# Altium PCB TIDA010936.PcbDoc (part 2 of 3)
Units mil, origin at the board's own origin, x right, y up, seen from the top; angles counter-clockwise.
Board outline 2755.91 x 2708.83 mil, 4 copper layers (Top Layer, POWER, GND, Bottom Layer), stack 64.224 mil thick; 224 components, 104 nets, 583 pads, 419 vias.

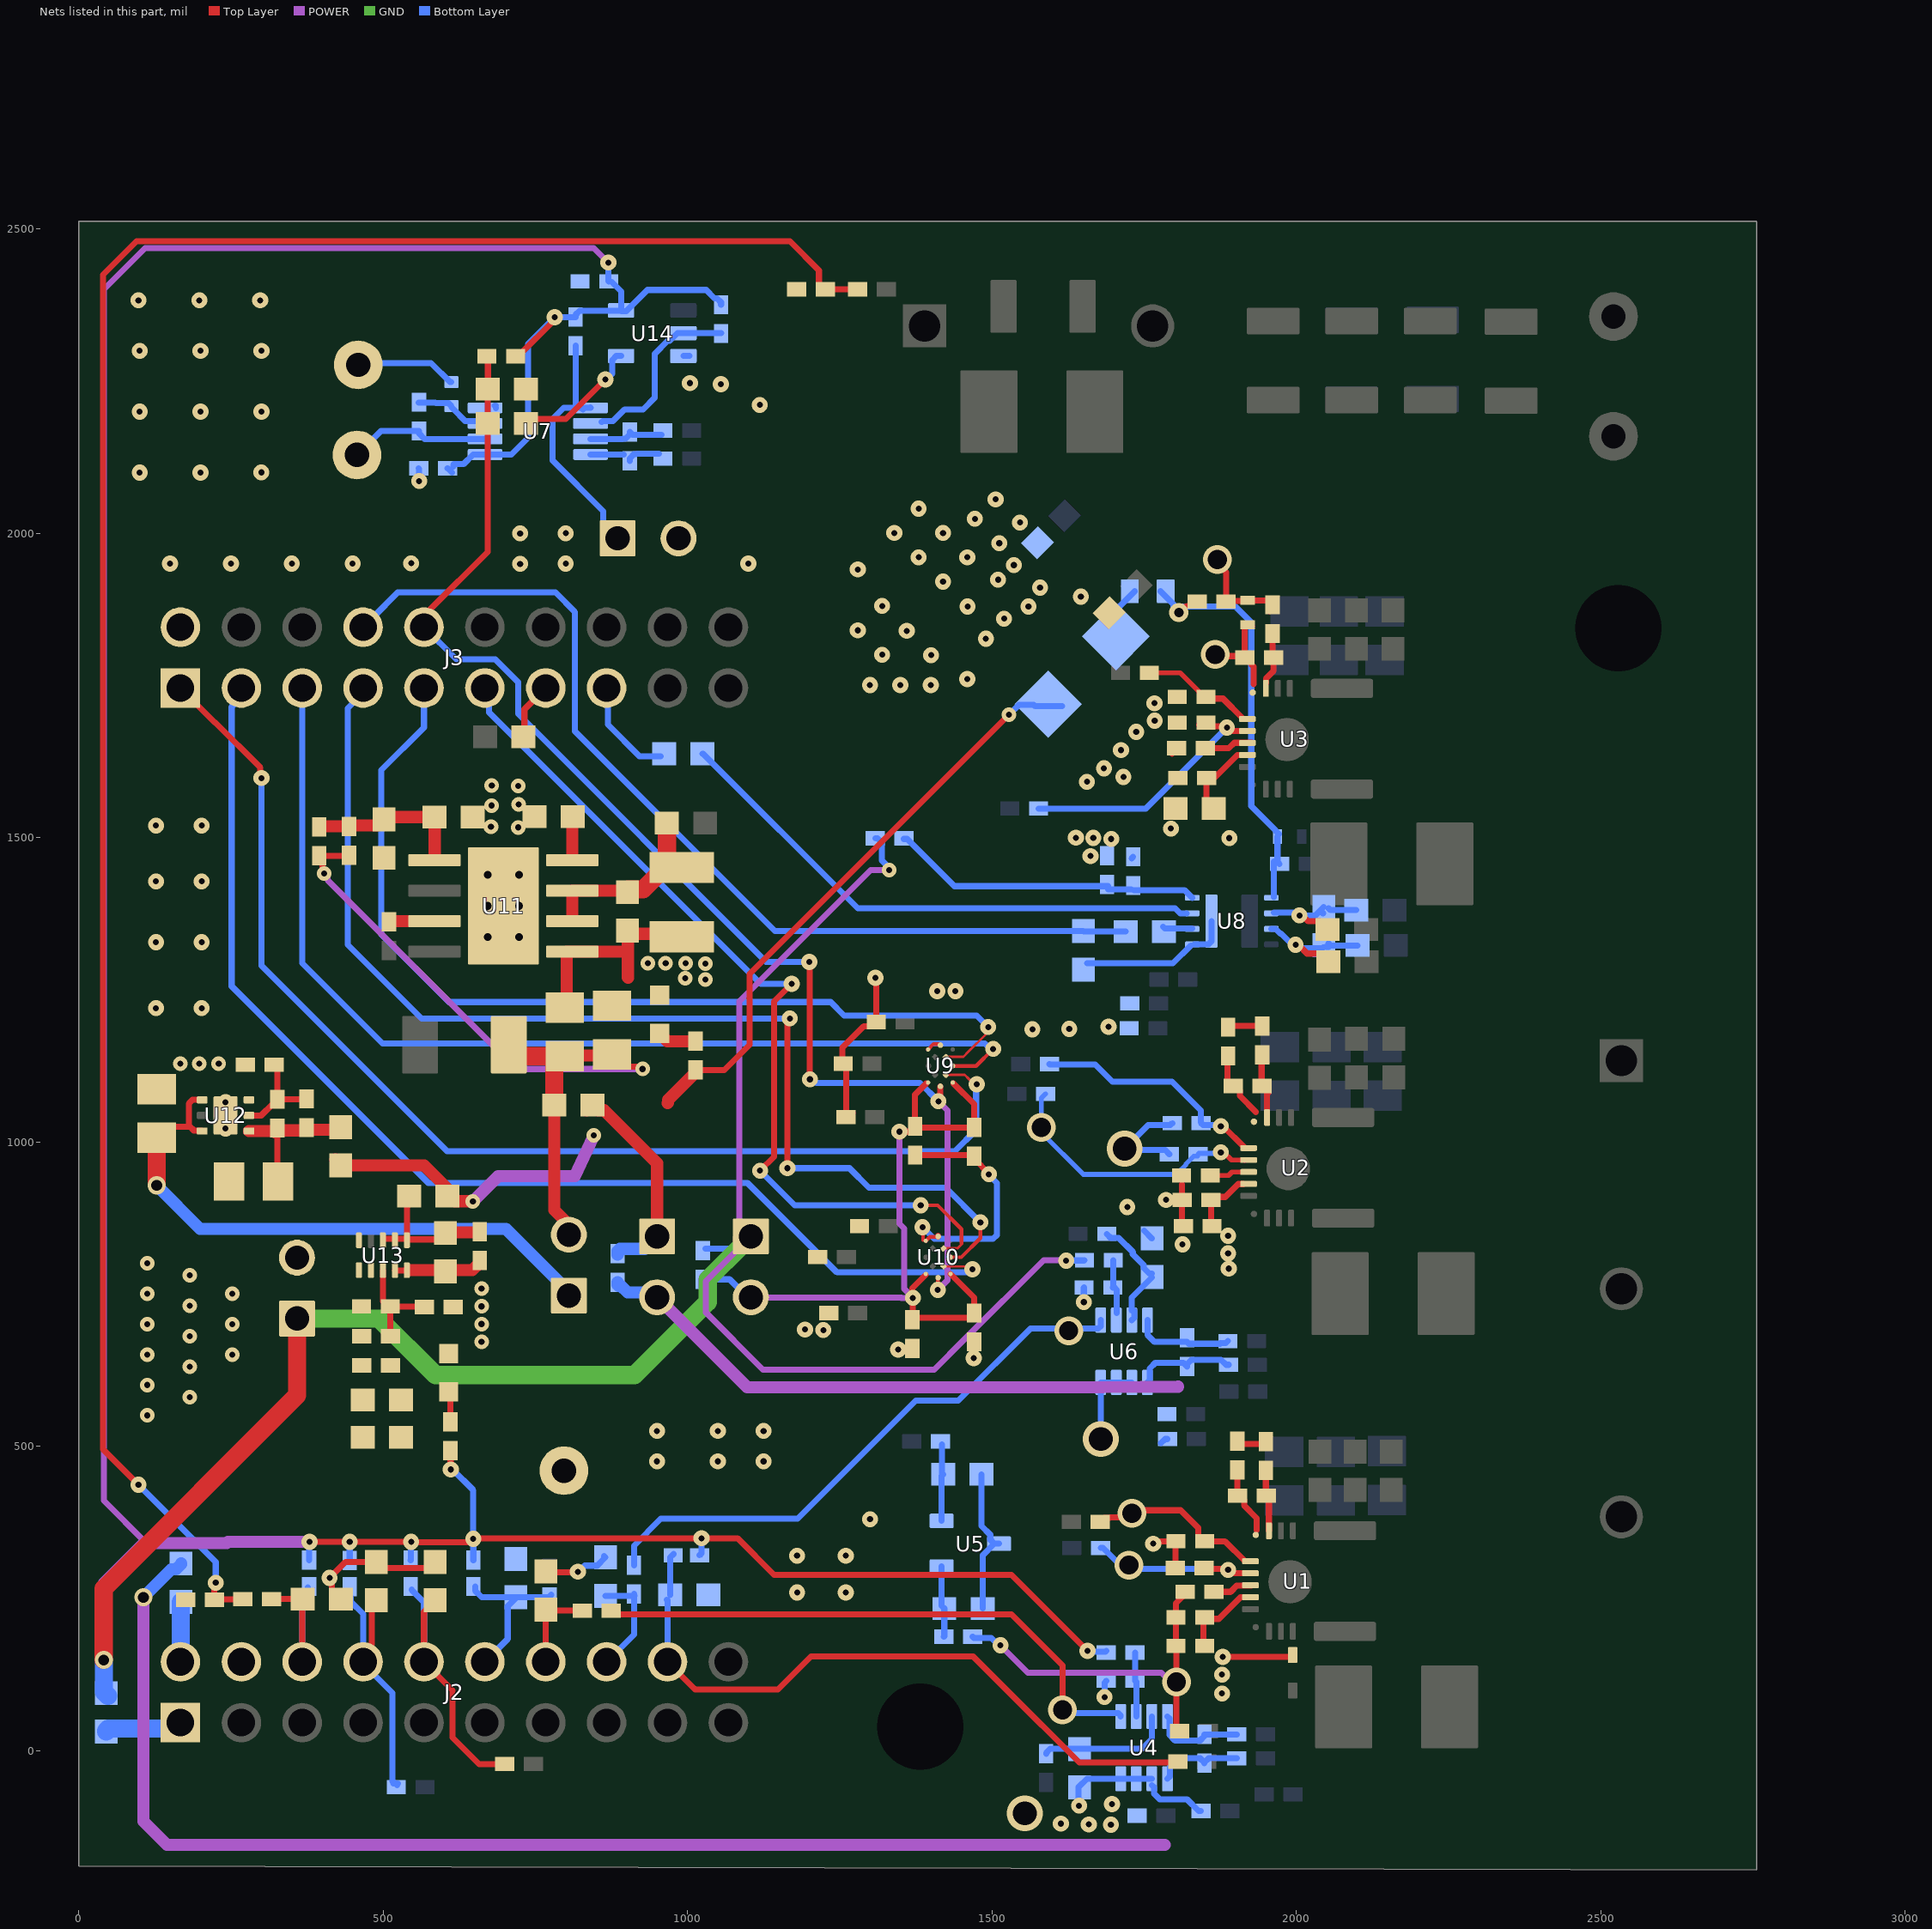
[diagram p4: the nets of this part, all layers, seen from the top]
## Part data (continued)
J1 J4 J7 J8: "Header, 100mil, 2x1, Tin, TH", Color=Black, Current_A=3A, Manufacturer="Sullins Connector Solutions", PartNumber=PEC02SAAN, Supplier Part Number 1=S1012E-02-ND, Voltage_V=1.8kV
J2 J3: "Connector, Receptacle, 100mil, 10x2, Gold plated, TH", Manufacturer=Samtec, PartNumber=SSW-110-23-F-D
J5: library part CMP-0055528-1, "Terminal Block, 9.52mm, 3x1, R/A, TH", Color=Green, Current_A=32A, Manufacturer="Phoenix Contact", PartNumber=1904150, Supplier Part Number 1=277-6184-ND, Voltage_V=1kV
J6: library part CMP-0055527-1, "Terminal Block, 9.52mm, 2x1, R/A, TH", Color=Green, Current_A=32A, Manufacturer="Phoenix Contact", PartNumber=1902547, Supplier Part Number 1=277-5951-ND, Voltage_V=1kV
J9: library part CMP-0002337-1, "Header, 100mil, 2x1, Tin, TH", Color=Black, Current_A=3A, Manufacturer="Sullins Connector Solutions", PartNumber=PEC02SAAN, Supplier Part Number 1=S1012E-02-ND, Voltage_V=1.8kV
L1 L2 L3: "Ferrite Bead, 300 ohm @ 100 MHz, 0.2 A, 0402", Manufacturer="Wurth Elektronik", PartNumber=74279272, Supplier Part Number 1=732-1572-1-ND, Value1="0.8 ohm", Value2=0.2A, ValueDisplayed="300 ohm"
L4: library part CMP-0064489-2, "Inductor, Shielded Drum Core, Powdered Iron, 22 uH, 1 A, 0.47 ohm, SMD", Manufacturer="Wurth Elektronik", Supplier Part Number 1=732-3340-1-ND, Value1="0.47 ohm", Value2=1A, ValueDisplayed=22uH
LBL1: library part CMP-0003625-1, "Thermal Transfer Printable Labels, 0.650\" W x 0.200\" H - 10,000 per roll", Manufacturer=Brady, Supplier Part Number 1=97C5133
NT1 NT2: "Single point connection between nets.", Manufacturer=N/A
R1 R18 R26 R39: library part CMP-0042666-1, "Res Metal Strip 2512 0.001 Ohm 1% 3W ±50ppm/C Pad SMD Automotive T/R", Manufacturer="TT Electronics", Mouser Part Number=66-ULRG3R001FLFSLT, Operating Temperature Range=to, Power_W=3W, Tempco=50ppm/°C, Tolerance_%=1%
R3 R4 R5 R13 R14 R23 R24 R25 R28 R30 R31 R32 R35 R36 R37 R52: "RES, 0, 5%, 0.063 W, AEC-Q200 Grade 0, 0402", Manufacturer=Vishay-Dale, PartNumber=CRCW04020000Z0ED, Power_W=63mW, Supplier Part Number 1=541-0.0JCT-ND, Tempco="200 ppm/C", Tolerance_%=5%, Value2=0.063W, Value_Code=0000, ValueDisplayed=0
R6 R7 R15: library part CMP-0026925-3, "RES, 3.0, 5%, 0.063 W, AEC-Q200 Grade 0, 0402", Manufacturer=Vishay-Dale, Power_W=63mW, Supplier Part Number 1=541-3.0JCT-ND, Tempco="200 ppm/C", Tolerance_%=5%, Value2=0.063W, Value_Code=3R00, ValueDisplayed=3.0
R8 R9 R10 R11 R16 R17: "RES, 20.0, 1%, 0.063 W, AEC-Q200 Grade 0, 0402", Manufacturer=Vishay-Dale, PartNumber=CRCW040220R0FKED, Power_W=63mW, Supplier Part Number 1=541-20.0LCT-ND, Tempco="100 ppm/C", Tolerance_%=1%, Value2=0.063W, Value_Code=20R0, ValueDisplayed=20.0
R12 R43 R58 R59 R60 R61 R62 R63 R70 R79: "RES, 10 k, 5%, 0.063 W, AEC-Q200 Grade 0, 0402", Manufacturer=Vishay-Dale, PartNumber=CRCW040210K0JNED, Power_W=63mW, Supplier Part Number 1=541-10KJCT-ND, Tempco="200 ppm/C", Tolerance_%=5%, Value2=0.063W, Value_Code=10k0, ValueDisplayed=10k
R19 R20 R27 R42: "RES, 100 k, 1%, 0.063 W, AEC-Q200 Grade 0, 0402", Manufacturer=Vishay-Dale, PartNumber=CRCW0402100KFKED, Power_W=63mW, Supplier Part Number 1=541-100KLCT-ND, Tempco="100 ppm/C", Tolerance_%=1%, Value2=0.063W, Value_Code=100k
R21 R22 R29 R46: "RES, 4.22 k, 1%, 0.063 W, AEC-Q200 Grade 0, 0402", Manufacturer=Vishay-Dale, PartNumber=CRCW04024K22FKED, Power_W=63mW, Supplier Part Number 1=541-4.22KLCT-ND, Tempco="100 ppm/C", Tolerance_%=1%, Value2=0.063W, Value_Code=4k22, ValueDisplayed=4.22k
R33: library part CMP-0026041-3, "RES, 16.5 k, 1%, 0.063 W, AEC-Q200 Grade 0, 0402", Manufacturer=Vishay-Dale, Power_W=63mW, Supplier Part Number 1=541-16.5KLCT-ND, Tempco="100 ppm/C", Tolerance_%=1%, Value2=0.063W, Value_Code=16k5, ValueDisplayed=16.5k
R34: library part CMP-0096630-1, "RES Thick Film, 3Ω, 1%, 0.33W, 100ppm/°C, 0603", Manufacturer=Vishay, Operating Temperature Range="-55°C to +155°C", Power=250mW, Power_W=330mW, Tempco=100ppm/°C, Tolerance_%=1%
R38: library part CMP-0093921-1, "11 kOhms ±1% 0.063W, 1/16W Chip Resistor 0402 (1005 Metric) Automotive AEC-Q200 Thick Film", Digikey Part Number=RMCF0402FT11K0CT-ND, Manufacturer=Stackpole, Operating Temperature Range="-55°C to +155°C", Power_W=63mW, Tempco=100ppm/°C, Tolerance_%=1%
R40 R56 R80: library part CMP-0022479-4, "RES, 50, 1%, 0.1 W, AEC-Q200 Grade 0, 0603", Manufacturer=Vishay-Dale, Power_W=100mW, Supplier Part Number 1=89M6778, Tempco="100 ppm/C", Tolerance_%=1%, Value2=0.1W, Value_Code=50R0, ValueDisplayed=50
R41 R45: library part CMP-0022004-2, "RES, 10.0, 1%, 0.25 W, 0603", Manufacturer=Vishay-Dale, Power_W=250mW, Supplier Part Number 1=541-10.0SCT-ND, Tempco="100 ppm/C", Tolerance_%=1%, Value2=0.25W, Value_Code=10R0, ValueDisplayed=10.0
R44: library part CMP-0025899-5, "RES, 1.0 k, 5%, 0.1 W, 0603", Manufacturer=Yageo, Power_W=100mW, Supplier Part Number 1=311-1.0KGRCT-ND, Tempco="100 ppm/C", Tolerance_%=5%, Value2=0.1W, Value_Code=1k00, ValueDisplayed=1.0k
R47 R48 R64 R65 R72 R73: library part CMP-0086358-1, "RES, 0, 0%, 0.25 W, AEC-Q200 Grade 0, 0603", Manufacturer=Rohm, Power_W=250mW, Tolerance_%=0%, Value2=0.25W, Value_Code=0000, ValueDisplayed=0
R49 R50 R51 R53 R54 R55 R57: "RES, 20, 5%, 0.063 W, AEC-Q200 Grade 0, 0402", Manufacturer=Vishay-Dale, PartNumber=CRCW040220R0JNED, Power_W=63mW, Supplier Part Number 1=541-20JCT-ND, Tempco="200 ppm/C", Tolerance_%=5%, Value2=0.063W, Value_Code=20R0, ValueDisplayed=20
R66: "RES, 1.2 k, 5%, 0.063 W, AEC-Q200 Grade 0, 0402", Manufacturer=Vishay-Dale, PartNumber=CRCW04021K20JNED, Power_W=63mW, Supplier Part Number 1=541-1.2KJCT-ND, Tempco="200 ppm/C", Tolerance_%=5%, Value2=0.063W, Value_Code=1k20, ValueDisplayed=1.2k
R67: library part CMP-0026367-2, "RES, 40.2 k, 1%, 0.063 W, AEC-Q200 Grade 0, 0402", Manufacturer=Vishay-Dale, Power_W=63mW, Supplier Part Number 1=541-40.2KLCT-ND, Tempco="100 ppm/C", Tolerance_%=1%, Value2=0.063W, Value_Code=40k2, ValueDisplayed=40.2k
R68: library part CMP-0022620-2, "RES, 82.5 k, 1%, 0.1 W, 0603", Manufacturer=Vishay-Dale, Power_W=100mW, Supplier Part Number 1=541-82.5KHCT-ND, Tempco="100 ppm/C", Tolerance_%=1%, Value2=0.1W, Value_Code=82k5, ValueDisplayed=82.5k
R69: library part CMP-0022418-4, "RES, 42.2 k, 1%, 0.1 W, AEC-Q200 Grade 0, 0603", Manufacturer=Vishay-Dale, Power_W=100mW, Supplier Part Number 1=541-42.2KHCT-ND, Tempco="100 ppm/C", Tolerance_%=1%, Value2=0.1W, Value_Code=42k2, ValueDisplayed=42.2k
R71: library part CMP-0080488-1, "RES, 10.0 k, 1%, 0.1 W, 0603", Manufacturer="TT Electronics/IRC", Power_W=100mW, Tempco="100 ppm/C", Tolerance_%=1%, Value2=0.1W, Value_Code=10k0, ValueDisplayed=10.0k
R74: library part CMP-0025971-3, "RES, 115 k, 1%, 0.063 W, AEC-Q200 Grade 0, 0402", Manufacturer=Vishay-Dale, Power_W=63mW, Supplier Part Number 1=541-115KLCT-ND, Tempco="100 ppm/C", Tolerance_%=1%, Value2=0.063W, Value_Code=115k
R75: "RES, 820, 5%, 0.063 W, AEC-Q200 Grade 0, 0402", Manufacturer=Vishay-Dale, PartNumber=CRCW0402820RJNED, Power_W=63mW, Supplier Part Number 1=541-820JCT-ND, Tempco="200 ppm/C", Tolerance_%=5%, Value2=0.063W, Value_Code=820R, ValueDisplayed=820
R76: library part CMP-0026046-3, "RES, 174 k, 1%, 0.063 W, AEC-Q200 Grade 0, 0402", Manufacturer=Vishay-Dale, Power_W=63mW, Supplier Part Number 1=541-174KLCT-ND, Tempco="100 ppm/C", Tolerance_%=1%, Value2=0.063W, Value_Code=174k
R77: library part CMP-0026171-2, "RES, 21.5 k, 1%, 0.063 W, AEC-Q200 Grade 0, 0402", Manufacturer=Vishay-Dale, Power_W=63mW, Supplier Part Number 1=541-21.5KLCT-ND, Tempco="100 ppm/C", Tolerance_%=1%, Value2=0.063W, Value_Code=21k5, ValueDisplayed=21.5k
R78: library part CMP-0026201-2, "RES, 25.5 k, 1%, 0.063 W, AEC-Q200 Grade 0, 0402", Manufacturer=Vishay-Dale, Power_W=63mW, Supplier Part Number 1=541-25.5KLCT-ND, Tempco="100 ppm/C", Tolerance_%=1%, Value2=0.063W, Value_Code=25k5, ValueDisplayed=25.5k
RT1: library part CMP-0091865-2, "±1% tolerance 10kΩ linear thermistor available in 0402 and 0603 package options 2-SOT-5X3 -40 to 125", Digikey Part Number=296-TMP6131DYATCT-ND, Manufacturer="Texas Instruments", Max Current=400uA, Mouser Part Number=595-TMP6131DYAT, Operating Temperature Range="-40°C to +125°C", Tempco=6400ppm/°C, Tolerance_%=1%
TP1 TP2: library part CMP-0055137-1, "Test Point, Miniature, Red, TH", Color=Red, Manufacturer=Keystone, Supplier Part Number 1=36-5000-ND
TP3 TP4 TP5: "Test Point, Miniature, Black, TH", Color=Black, Manufacturer="Keystone Electronics", PartNumber=5001, Supplier Part Number 1=36-5001-ND
U1 U2 U3: library part CMP-0097820-2, Manufacturer="Texas Instruments", Operating Temperature Range=to
U4 U6: library part CMP-0093649-2, "-4-V to 110-V, Bidirectional, Ultra-Precise Current Sense Amplifier With Enhanced PWM Rejection", Input Bias Current=40uA, Input Offset Voltage=0.002mV, Manufacturer="Texas Instruments", Max Supply Voltage=20V, Min Supply Voltage=2.7V, Nominal Supply Current=2.5mA, Operating Temperature Range="-40°C to +125°C", Voltage Gain=0.05V/mV
U5: library part CMP-0032556-1, "30 ppm / degC Drift, 3.9 uA Voltage Reference, -40 to 125 degC, 3-pin SOT-23 (DBZ), Green (RoHS & no Sb/Br)", Manufacturer="Texas Instruments", Rating=Catalog, Temp Coeff(Max)(ppm/ degree C)=30, Temp Coeff(Typ)(ppm/ degree C)=8
U7: library part CMP-0095220-1, "-4V to 110V, 1.3-MHz, Ultra-Precise Current Sense Amplifier With OpenDrain Comparator and Reference", Input Bias Current=20uA, Input Offset Voltage=0.015mV, Manufacturer="Texas Instruments", Max Supply Voltage=20V, Min Supply Voltage=2.7V, Nominal Supply Current=1.5mA, Operating Temperature Range="-40°C to +125°C", Voltage Gain=0.05V/mV
U8: library part CMP-0049066-2, "±50 mV Input Functionally Isolated Delta-Sigma Modulator for Current Sensing, VSON8", Manufacturer="Texas Instruments", Operating Temperature Range="-40°C to +125°C", Part Number=AMC0106DENR
U9 U10: library part CMP-0091905-2, "4-Bit Fixed Direction Voltage-Level Translator with SchmittTrigger Inputs, and Tri-State Outputs", Manufacturer="Texas Instruments", Operating Temperature Range=to
U11: library part CMP-0096892-1, "4.2-V to 80-V, 1-A Synchronous Buck Converter with 40-µA IQ", Manufacturer="Texas Instruments", Max Supply Voltage=80V, Min Supply Voltage=4.2V, Mouser Part Number=595-LMR38010FDDAR, Nominal Supply Current=40uA, Operating Temperature Range="-40°C to +150°C", Output Voltage=1-75V, Switching Frequency=200-2200kHz
U12: library part CMP-0085198-1, "1-A LDO With Power-Good, DRV0006A (WSON-6)", Alternate Manufacturer="Texas Instruments", Operating Temperature Range="-40 to 125 C"
U13: library part CMP-0092387-1, "1-A High Efficiency Step-Down Converter MicroSiP Power Module with Integrated Inductor", Manufacturer="Texas Instruments", Max Supply Voltage=5.5V, Min Supply Voltage=2.4V, Nominal Supply Current=4uA, Operating Temperature Range="-40°C to +125°C", Output Voltage=0.6-4V, Switching Frequency=4MHz
U14: library part CMP-0859-00032-5, "IC INVERTER SCHMITT 1CH SOT23-5", Ambient Temperature Range High=+125°C, Ambient Temperature Range Low=-40°C, Manufacturer="Texas Instruments", Max Junction Temp=+150°C, Max Supply Voltage=5.5V, Min Supply Voltage=1.65V, Nominal Supply Current=10uA, Package=DBV0005A, Temperature="-40°C to +125°C"

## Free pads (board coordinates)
  round 60 hole 141.73: 5(1382,39.37) 5(2529.26,1844.26)

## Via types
v1: diameter 26.38, hole 10, Top Layer to Bottom Layer, 310 vias
v2: diameter 19.68, hole 10, Top Layer to Bottom Layer, tented both sides, 45 vias
v3: diameter 24, hole 10, Top Layer to Bottom Layer, tented both sides, 39 vias
v4: diameter 47.24, hole 31.5, Top Layer to Bottom Layer, 10 vias
v5: diameter 24.8, hole 12.99, Top Layer to Bottom Layer, tented both sides, 6 vias
v6: diameter 59.06, hole 39.37, Top Layer to Bottom Layer, 5 vias
v7: diameter 29.68, hole 17.87, Top Layer to Bottom Layer, 3 vias
v8: diameter 31.5, hole 15.75, Top Layer to Bottom Layer, 1 vias

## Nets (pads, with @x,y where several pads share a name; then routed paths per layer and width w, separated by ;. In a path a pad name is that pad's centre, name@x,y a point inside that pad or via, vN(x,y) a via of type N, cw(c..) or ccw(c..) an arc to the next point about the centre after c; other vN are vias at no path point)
3V3: C55.2 C93.1 D2.1 D3.1 D4.1 D5.1 D6.1 J4.1 J8.1 L1.1 L3.1 R37.2 R43.2 R48.2 R52.2 R70.2 R75.2 R79.1 U7.1 U14.5 | length 9405.4
  Top Layer w10: v1(379,343) v1(546,343) 546.45,342.55 638.12,342.55 643.57,348 v1(648,348) ; v1(611,462) 610.75,462.25 610.75,484.75 R75.2@611,485 ; v1@658.75,349 v1(1023,349) 1082,349 1142,289 1532,289 v1(1657,164) v1@1658,164 ; R43.2@718,2293 723.56,2293 781.61,2351.05 v1(781.61,2355.15)
  Top Layer w30: v7(41,149) 41,266.34 358.51,583.85 J8.1@358.51,710
  POWER w10: 110.66,341 41,410.66 41,2401 109,2469 846,2469 v1(870,2445) ; J4.1@1102,843 1030,771 1030,720 1124,626 1405,626 1454,675 1584.87,805.87 1621.13,805.87 v1(1622,805) ; J4.1@1104,845 1085,864 1085,1231 1301,1447 v3(1331,1447)
  POWER w20: v7(41,149) 41,275 107,341 110.66,341 242.97,341 244.97,343 v1(379,343)
  GND w30: J8.1@358.51,710 493,710 586,617 913,617 1033,737 1033,774 1089.47,830.47 1089.47,841.47 J4.1@1095,847
  Bottom Layer w10: D2.1@378.16,313.11 378.58,313.53 378.58,342.58 v1(379,343) ; D5.1@445,312.65 v1(445,343) ; D3.1@545.16,312.96 545.58,313.38 545.58,342.58 v1(546,343) ; C55.2@605.62,2107 606.19,2107 C55.2@613,2100.19 ; v1(611,462) 614,462 648,428 v1(648,348) ; C55.2@615,2110 615,2112.44 616.37,2113.81 631.9,2113.81 647.7,2129.61 U7.1@667.39,2129.61 710.61,2129.61 738,2157 738,2311.54 v1(781.61,2355.15) 782,2355.54 v1@782,2359 ; D6.1@648.16,312.97 648.08,313.05 648.08,344.08 v1@649,345 ; v1@786,2355 815.38,2355 R79.1@816,2355.62 816,2359.19 822.81,2366 U14.5@890.82,2366 ; v1(870,2445) 870,2414.62 C93.1@870.62,2414 ; C93.1@875.56,2413 890.82,2397.74 U14.5@890.82,2366.4 ; U14.5@891,2365 899.26,2365 934.26,2400 1030.62,2400 1044.25,2386.37 1048.19,2386.37 1055,2379.56 R70.2@1055,2375.62 ; D4.1@1019.65,321 1023,324.35 v1(1023,349) ; R52.2@1029,825 1084,825 J4.1@1104,845 ; R37.2@1308.38,1499 1312.32,1499 1319.13,1492.19 1319.13,1462.66 1331,1450.79 v3(1331,1447) ; v1(1622,805) 1622.43,805.43 1651.56,805.43 L3.1@1652,805.87 ; v1(1657,164) 1658.45,162.55 1686.55,162.55 L1.1@1688,164
  Bottom Layer w30: v7(41,149) 41.3,148.7 41.3,96.7 R48.2@48,90
"3V3_PWM Buffer": C67.1 C72.1 C76.2 C77.1 J4.2 R52.1 U9.1 U9.11 U10.1 U10.11 | length 1191.1
  Top Layer w6: C72.1@1366.44,1018.56 C72.1@1371.44,1023.56 ; 1387.5,779.32 U10.11@1389,780.82 ; U9.1@1435.62,1097.83 U9.1@1437.23,1096.23
  Top Layer w10: v1(1348,1017) 1366.87,1017 1367,1017.13 C72.1@1367,1018 ; C77.1@1369,720 1370.18,721.18 v1(1370.18,743.87) ; C77.1@1369.34,707.87 1372.47,711 C76.2@1472,711 ; v1@1369.34,743.87 1369.34,760.16 U10.11@1391,782 ; C72.1@1371.14,1023.86 C67.1@1470.68,1023.86 1470.68,1062.32 U9.1@1437,1096 ; C72.1@1373.68,1025.86 1373.68,1077.68 1392,1096 ; U10.1@1432,783 1470.68,744.32 C76.2@1470.68,718.98
  POWER w10: J4.2@1104,745 1104.57,744.43 1351.28,744.43 ; v1(1348,1017) 1348,865.87 1356,857.87 1356,758.91 1370.18,744.73 v1(1370.18,743.87) 1351.28,743.87
  Bottom Layer w10: R52.1@1025,774.38 1069.01,774.38 1098.39,745 J4.2@1105,745
3V3Lauchpad: J2.1 R48.1 | length 126.9
  Bottom Layer w30: R48.1@45,31.5 45,32.49 48.7,36.19 168.19,36.19 J2.1@169,37
5.5VLDO: C83.1 J7.1 U12.4 U12.6 | length 969
  Top Layer w10: C83.1@130,1006 149,1025 180,1025 ; 180.88,1027.01 180.88,1063.45 186.74,1069.31 U12.4@202.61,1069.31 ; 181.44,1026.44 188.86,1019.03 201.71,1019.03 U12.6@202.61,1018.13
  Top Layer w30: v7@128,935.57 C83.1@128,1007
  Bottom Layer w20: v7@125,932 v7@127,930 ; v7@128,931 128,928.73 199.33,857.4 701.6,857.4 J7.1@805,754
  other v7: 127.88,928.84
5V: D1.2 J1.1 R3.1 R65.1 R66.1 R72.1 R73.2 | length 1911.9
  Top Layer w10: R66.1@1013,1118.38 1060.38,1118.38 1102,1160 1102,1276 1526,1700 v3@1529,1700 ; v3@1527.5,1701.5 v3(1528,1702)
  Top Layer w20: R72.1@421.3,971.19 R72.1@426,966.49 ; R72.1@430,961.5 567.5,961.5 R73.2@604,925 ; R73.2@618.18,902.68 647,902.68 v3(647.31,902.37) ; R65.1@834.3,1052.3 843,1061 R65.1@843.99,1061 852.69,1052.3 862.7,1052.3 950,965 ; 893,1022 950,965 ; J1.1@950,845 950,965 ; 967,1064 967.77,1064.77 967.77,1069.21 R66.1@1013,1114.44
  POWER w20: v3(647.31,902.37) 688.95,944 815,944 v3@845,1009
  Bottom Layer w10: v3(1528,1702) 1544.52,1718.52 1568.48,1718.52 1571,1716 D1.2@1615,1716
  Bottom Layer w20: R3.1@885,815 R3.1@885,816.62 885,820.56 888.93,824.49 929.49,824.49 J1.1@950,845
  other v3: 846,1011
5VGAN: C11.1 C12.2 C14.1 C20.1 C35.1 C37.2 J1.2 L2.2 R3.2 R4.2 R5.2 R12.2 R13.2 R47.1 | length 3828.5
  Top Layer w10: C20.1@1792.5,218.5 C20.1@1793,218 ; C35.1@1796.01,1558.81 1802.82,1552 C35.1@1806.76,1552 ; R13.2@1796.01,1638.19 R13.2@1802.41,1644.59 ; C14.1@1802,165.19 1803,165.19 1803,37.38 R12.2@1808.38,32 ; C14.1@1802,172 1802,218.62 C20.1@1802.38,219 1802.38,242.38 R5.2@1821,261 ; R13.2@1803,1644 R13.2@1804,1645 ; C11.1@1812.38,860.62 C12.2@1812.38,905 1812.38,930.38
  POWER w10: v1(1514,173) 1559,128 1778.52,128 1786.09,120.43 1786.92,120.43 v4@1794.5,128
  POWER w20: v7(106,252) 106,-116 145,-155 1784,-155 ; J1.2@950,745 1098,597 1682,597 1806,598
  Bottom Layer w10: L2.2@1468.27,187.13 1470.04,185.36 1499.02,185.36 1511.38,173 v1(1514,173)
  Bottom Layer w20: v7(106,252) 151.81,297.81 159.3,297.81 168,306.51 R47.1@168,307.5 ; R3.2@885,769.38 885,765.44 886.81,763.63 890.75,763.63 901.53,752.85 939.15,752.85 J1.2@950,742
  other v1: 1813,832 1786,905 1794,1515
  other v4: 1803,113
AH: J3.1 U9.2 | length 1971.1
  Top Layer w4: U9.2@1424.01,1110.43 1424.43,1110.02 1427.16,1110.02 1427.58,1110.43 1455.32,1110.43 1462,1103.76 1469.76,1096 v1@1475,1096
  Top Layer w6: v1@1473.3,1095 v1(1475,1095)
  Top Layer w10: J3.1@167,1746 223.28,1689.72 223.76,1689.72 298.15,1615.33 298.15,1599.85 v1(300,1598)
  Bottom Layer w10: J3.1@157.62,1738.62 J3.1@165,1746 ; v1(300,1598) 300,1290 605,985 1439,985 1473.93,1019.93 1473.93,1093.93 v1(1475,1095)
AL: J3.3 U10.2 | length 1957.2
  Top Layer w4: U10.2@1420.69,795.61 1459.15,795.61 1463.76,791 v1(1468,791)
  Bottom Layer w10: J3.3@267,1746 267,1731.13 251,1715.13 251,1256 574,933 1098,933 1244,787 ; 1246,786 1460.38,786 1465.38,791 v1(1468,791)
BH: J3.5 U9.3 | length 1724
  Top Layer w6: U9.3@1435.03,1125 1474,1125 v1(1502,1153)
  Bottom Layer w10: J3.5@367,1746 367,1294 499,1162 1335,1162 1462,1162 1488.57,1162 1497.57,1153 v1(1502,1153)
BL: J3.7 U10.3 | length 1898.7
  Top Layer w6: U10.3@1431.3,810.59 1449.59,810.59 1481,842 v1(1481,868)
  Top Layer w10: v1(1164,957) 1164,1196.38 1168,1200.38 v1(1168,1203)
  Bottom Layer w10: J3.7@467,1746 467,1737.66 442,1712.66 442,1324 563,1203 v1(1168,1203) ; v1(1164,957) 1266,957 1298,925 1424,925 v1(1481,868)
BOOT: C78.2 U11.7 | length 73.5
  Top Layer w20: C78.2@512.49,1359 516.49,1363 U11.7@584.3,1363
BS_AMC: C56.1 C57.1 R14.2 R34.1 U8.1 | length 686.1
  Top Layer w10: v8@1802,1876 R14.2@1842,1886
  Bottom Layer w10: R34.1@1776.67,1905 1799,1882.67 v8@1799,1880 ; v8@1798,1880 1900,1880 1926,1854 1926,1552 1965.63,1512.37 1965.63,1511.81 C57.1@1971.44,1506 ; U8.1@1962.93,1402.39 C56.1@1962.93,1461 ; C57.1@1969,1502 1969,1460.38 C56.1@1972.38,1457
  other v8: 1807,1870
CH: J3.9 U9.4 | length 1588.9
  Top Layer w4: U9.4@1424.43,1139.98 1452.98,1139.98 1462,1149 1489.58,1176.58 1489.58,1184.69 v1(1493.86,1188.97)
  Top Layer w6: U9.4@1424.01,1139.57 U9.4@1424.43,1139.98
  Bottom Layer w10: J3.9@567,1746 567,1681 497,1611 497,1341 608,1230 1235,1230 1257,1208 1474.84,1208 v1(1493.86,1188.97)
CL: J3.11 U10.4 | length 1480.9
  Top Layer w4: U10.4@1420.27,825.16 1420.69,825.57 1443.57,825.57 1451,833
  Top Layer w6: v1(1383,896) 1411,896 1450.05,856.95 1450.05,834
  Top Layer w10: v1(1119,953) 1141.94,975.94 1141.94,1230.94 v1(1171,1260)
  Bottom Layer w10: J3.11@667,1746 674.07,1738.93 674.07,1705.93 1120,1260 v1(1171,1260) ; v1(1119,953) 1176,896 v1(1383,896)
CLK_PhC: R80.1 U8.7 | length 903.8
  Bottom Layer w10: R80.1@1024.5,1638 1025.48,1638 1279.48,1384 1801.09,1384 1809.21,1375.87 U8.7@1819.69,1375.87
DAT_PhC: C62.1 J3.8 R40.1 | length 1610.3
  Bottom Layer w10: J3.8@471,1862 483,1862 524,1903 783,1903 815,1871 815,1675 1143.5,1346.5 C62.1@1650,1346.5 ; C62.1@1650.5,1346 R40.1@1719.5,1346
DC_BUS_I: R33.2 TP2.1 U7.2 | length 240.4
  Bottom Layer w10: TP2.1@457,2129 496.38,2168.38 R33.2@559,2168.38 ; TP2.1@464,2122 TP2.1@471,2129 ; R33.2@559,2164.44 568.24,2155.2 U7.2@667.39,2155.2
DCBUS: C46.1 R20.1 R22.2 R49.1 | length 3604.5
  Top Layer w10: v1(98,437) 40,495 40,2425 95,2480 1168,2480 1215.87,2432.13 1215.87,2407.81 1222.68,2401 R20.1@1279.38,2401 ; v1@225,275 222.62,272.62 C46.1@222.62,248 223.12,248.5 265.5,248.5 R49.1@266,248
  Bottom Layer w10: v1(98,437) 224.91,310.09 224.91,278.09 v1@225,278
  other v1: 224.91,275.83
FB: C79.2 R67.1 R68.2 R71.2 U11.5 | length 238.3
  Top Layer w20: C79.2@401,1520 402.38,1518.62 R67.1@444,1518.62 ; R67.1@455.31,1520.31 492.79,1520.31 501.49,1529.01 R68.2@501.49,1529.99 ; R68.2@508,1534 R71.2@583.99,1534 ; U11.5@584.49,1466 R71.2@584.49,1534
GND: 1.2 C11.2 C12.1 C14.2 C20.2 C28.2 C29.2 C30.2 C31.2 C35.2 C37.1 C42.2 C43.2 C44.2 C45.1 C46.2 C48.1 C49.1 C50.2 C51.1 C52.2 C54.1 C55.1 C58.2 C59.2 C62.2 C63.2 C64.2 C67.2 C68.2 C69.2 C70.2 C71.2 C72.2 C73.2 C74.2 C75.2 C76.1 C77.2 C80.2 C81.2 C82.2 C83.2 C85.2 C86.2 C88.2 C89.2 C90.2 C91.2 C92.2 C93.2 D7.1 D8.1 J2.4 J3.2 J9.2 NT1.2 NT2.2 R2.2 R21.1 R22.1 R29.1 R38.2 R46.1 R58.1 R59.1 R60.1 R61.1 R62.1 R63.1 R68.1 R69.1 R71.1 R77.1 R78.1 RT1.1 TP3.1 TP4.1 U1.15 U2.15 U3.15 U4.2 U4.3 U4.4 U5.3 U6.2 U6.3 U6.4 U7.4 U8.5 U9.6 U9.7 U10.6 U10.7 U11.1 U11.9 U12.3 U12.7@241,1043.72 U13.9 U13.10 U14.3 | length 3501.3
  Top Layer w6: v1(1386,860) 1387,859 1387,839 ; U10.7@1391.34,837.76 1391.63,837.76 1398.01,844.14 1410.86,844.14 U10.6@1411,844 ; U9.7@1395.07,1152.17 U9.7@1395.07,1152.17 1403.98,1161 U9.6@1413,1161
  Top Layer w10: v1@412,279.57 415.81,275.76 415.81,262.7 429.51,249 C75.2@430.5,249 ; v1@412,286 414,286 437.99,309.99 C74.2@489,309.99 498.99,300 579,300 C73.2@580,301 ; U13.9@519.19,789.39 519.19,789.08 519.27,789 U13.10@542.51,789 ; C73.2@585,309.99 C73.2@592.99,302 ; C70.2@767,294.5 768.5,293 818,293 v1@819,292 ; R22.1@1178.88,2400.5 R22.1@1179.38,2401 ; R59.1@1257.44,1132 1254,1135.44 1254,1155 1289.24,1190.24 1303.27,1190.24 R60.1@1310.08,1197.05 1310.08,1259.92 v1@1309,1261 ; R59.1@1258,1127 1260.38,1124.62 R58.1@1260.38,1041 ; R58.1@1268.55,1045.23 R58.1@1271.13,1047.81 ; v1(1346,659) 1367.72,659 C77.2@1369.34,660.62 ; C72.2@1373.68,974.68 C72.2@1373.68,978.62 1467.38,978.62 C67.2@1470,976 ; U10.6@1411.61,844.75 U10.6@1411.61,845.75 ; v1(1470,645) 1470.34,645.34 1470.34,671.39 C76.1@1470.68,671.73 ; C67.2@1471.34,975.96 1471.34,972.02 1495,948.36 v1(1495,947) ; v1(1765,340) 1767.62,340 1771.62,344 C29.2@1801,344 ; C29.2@1801,343 1801.38,342.62 C31.2@1801.38,300 ; C42.2@1803.76,1730.68 C42.2@1804.44,1731.35 ; C43.2@1804.32,1685.12 C43.2@1804.44,1685.25 ; C14.2@1847.62,166 1847.62,211.62 C20.2@1848,212 ; C20.2@1848.62,212 1853.14,216.52 1872.87,216.52 1908.43,252.07 U1.15@1924.5,252.07 ; C37.1@1852.62,1598 1852.62,1553.38 1854,1552 C35.2@1857.94,1552 ; C37.1@1852.62,1599.16 1866.51,1599.16 1903.35,1635.99 U3.15@1910.72,1635.99 ; C12.1@1859.62,905 C12.1@1860,905 ; C11.2@1861.62,862 1860,863.62 C12.1@1860,905 ; v1(1879,154) 1991.13,154 1994,156.87 RT1.1@1994,157.13 ; U2.15@1912.72,930.99 1904.67,930.99 1883.54,909.86 1864.86,909.86 C12.1@1860,905
  Top Layer w20: U13.10@542.51,789.39 646.46,789.39 657.51,800.44 C86.2@657.51,801 ; C82.2@801.49,1227 801.49,1312.84 801.65,1313 U11.1@810.68,1313 900.49,1313 ; C81.2@901.99,1343 901.99,1270.5 902.49,1270 ; C81.2@903.49,1343 904.24,1342.25 985.24,1342.25 C80.2@990.49,1337
  Bottom Layer w10: TP3.1@462.6,2280 578.72,2280 610.03,2248.68 R38.2@612,2248.68 ; C55.1@558.38,2107 559,2106.38 v1(559,2086) ; U7.4@683,2210 U7.4@685,2210 ; U7.4@685,2206 U7.4@685.39,2206.39 ; v1@822,296 823,296 831,304 851.5,304 C69.2@865,317.5 C69.2@863,319.5 ; U14.3@993.18,2291.6 U14.3@1003.02,2291.6 ; v1(1386,860) 1405,841 1502,841 1508,847 1508,932.95 1495,945.95 v1(1495,947) ; C51.1@1482.76,453.86 1482.76,369.26 1497.2,354.82 1497.2,346.94 U5.3@1504.02,340.13 ; C50.2@1484.76,233.75 1484.76,320.88 U5.3@1504.02,340.13 ; U5.3@1511.89,340.13 U5.3@1504.02,340.13 ; v1@1643,-90 1642.36,-89.36 1642.36,-59.96 1656.07,-46.26 U4.4@1711.5,-46.26 U4.3@1737.09,-46.26 U4.2@1762.68,-46.26 ; v1(1651,737) 1651,760.62 C49.1@1651.38,761 ; C62.2@1656.45,1294 1797.46,1294 U8.5@1827,1323 ; v6@1679,511 1678.83,511.17 1678.83,604.83 U6.4@1678.67,604.99 U6.3@1704.26,604.99 U6.2@1729.85,604.99 ; v1(1685,88) 1685,111.97 C45.1@1687.88,114.85 ; C59.2@1729.38,1466 C59.2@1732,1468.62 ; C54.1@1750,854.5 C54.1@1763,841.5 ; U4.2@1763,-57 1766.54,-60.54 1766.54,-71.12 1775.22,-79.81 1820.25,-79.81 1839.44,-99 R21.1@1843.38,-99 ; R29.1@1777.63,505.19 1784.44,512 R29.1@1788.38,512 ; C30.2@1791.38,980 1784.57,986.81 1720.19,986.81 v6(1718,989) 1756.8,1027.8 1793.18,1027.8 C28.2@1796.38,1031 ; U8.5@1833,1325 1855.69,1325 1860.54,1329.84 U8.5@1860.54,1363
  other v1: 1695.44,-121.7 1659,-121.19 1613.18,-119.93 1643.03,-90.4 1697.18,-87.93 1878,94 1878,125 1180,260 1260,260 412,284 819.91,293.9 1179.81,320.32 1259.81,320.32 1299.81,380.32 949.81,475.32 1049.81,475.32 1124.81,475.32 949.81,525.32 1049.81,525.32 1124.81,525.32 1223,691 1193,692 1889,792 1888,817 1888,846 1722.41,893.23 241,1022.06 241,1065.37 1566.44,1185.32 1627,1186 1691.44,1189.32 126.81,1220 201.81,1220 1410,1248 1440,1248 1308.66,1269.74 126.81,1328.32 201.81,1328.32 126.81,1428.32 201.81,1428.32 1662,1470 1696,1498 1890,1499.45 1638,1500 1666.56,1499.78 126.81,1520 201.81,1520 1656,1592 1716,1600 1684,1614 1712,1644 1737,1674 1767.39,1692.22 1767,1721 1299.59,1750.76 1349.59,1750.76 1399.59,1750.76 1459.59,1760.76 1400,1800 1319.59,1800.76 1490,1827 1360,1840 1279.59,1840.76 1520,1860 1460,1880 1560,1880 1319.59,1880.76 1646,1896 1579,1911 1419.59,1920.76 1510,1924 1279.59,1940.76 1536,1948 149.81,1950.32 249.81,1950.32 349.81,1950.32 449.81,1950.32 725,1950 799.81,1950.32 1099.81,1950.32 546,1951 1379.59,1960.76 1459.59,1960.76 1512,1984 725,2000 799.81,2000.32 1339.59,2000.76 1419.59,2000.76 1546,2018 1472,2024 1379.59,2040.76 1506,2056 100,2100 200,2100 299.81,2100.32 100,2200 200,2200 300,2200 1118.61,2211.15 1054.61,2245.15 1004,2247 100,2300 200,2300 300,2300 98,2383 198,2383 298,2383
  other v3: 112.34,550.86 182.34,580.86 112.34,600.86 182.34,630.86 112.34,650.86 252.34,650.86 661.51,672 182.34,680.86 112.34,700.86 252.34,700.86 661.51,701 661.51,730 182.34,730.86 112.34,750.86 252.34,750.86 661.51,759 182.34,780.86 112.34,800.86 167,1129 198,1129 229.79,1129 1029,1267 996.19,1269.14 1029,1293 935,1294 964,1294 997,1294 722,1517 677,1518 678,1553 722.34,1554.86 722,1585 678.34,1585.86
  other v5: 671.9,1336.82 723.08,1336.82 671.9,1388 723.08,1388 671.9,1439.18 723.08,1439.18
  other v6: 1554,-103 1679,512
IA: R54.1 U4.5 | length 958.5
  Top Layer w10: R54.1@869,230 875,224 1532,224 1616,140 v4(1616,67)
  Bottom Layer w10: v4(1616,67) 1621.06,61.94 1707.64,61.94 1711.5,58.08 U4.5@1711.5,56.1
IB: R55.1 U6.5 | length 960.7
  Bottom Layer w10: R55.1@912,304.62 912,337 956,381 1181,381 1375,575 1444.87,575 1563.51,693.64 1622.36,693.64 v4(1626,690) ; v4@1625,693.64 1674.81,693.64 1678.67,697.49 U6.5@1678.67,707.36
NetC24_1: C24.1 R6.1 | length 58
  Top Layer w10: C24.1@1888,1188.62 1890.38,1191 R6.1@1945,1191
NetC24_2: C24.2 C25.2 U2.11 | length 99.3
  Top Layer w10: C24.2@1887,1131 1887,1098.81 1893.81,1092 C25.2@1896.38,1092 ; C25.2@1901.32,1091 1907.13,1085.19 1907.13,1075.87 1933.54,1049.46
NetC25_1: C25.1 R6.2 U2.10 | length 86
  Top Layer w10: C25.1@1943,1096 R6.2@1943,1133.38 ; C25.1@1943.62,1092 1947.56,1092 1954.37,1085.19 C25.1@1954.37,1081.25 ; R6.2@1949,1149 R6.2@1949.93,1148.07 ; U2.10@1952,1051 C25.1@1952,1080.84
NetC26_1: C26.1 R7.1 | length 49.8
  Top Layer w10: C26.1@1903,508.62 1907.62,504 R7.1@1950,504 ; R7.1@1948.38,509.62 R7.1@1949,509
NetC26_2: C26.2 C27.2 U1.11 | length 108
  Top Layer w10: C26.2@1903,458 1903,419.38 C27.2@1903.38,419 ; C27.2@1904,413 1913.32,413 1914.13,412.19 1914.13,402.87 1935,382 1935,362.41
NetC27_1: C27.1 R7.2 U1.10 | length 96.3
  Top Layer w10: C27.1@1949,423 1950,424 R7.2@1950,460.38 ; C27.1@1950.62,419 C27.1@1951.81,420.19 ; C27.1@1955.01,417.99 U1.10@1955.01,361.33 U1.10@1955.09,361.4
NetC28_1: C28.1 R8.1 U2.12 | length 384.2
  Top Layer w10: v1(1876,1026) 1880,1026 U2.12@1915,991
  Bottom Layer w10: R8.1@1594.62,1128 1595.12,1127.5 1669.5,1127.5 1698,1099 1796,1099 1843,1052 C28.1@1843,1032 ; C28.1@1843.62,1031 1846.77,1027.85 v1@1873.15,1027.85
NetC29_1: C29.1 R9.1 U1.12 | length 284.8
  Top Layer w10: R9.1@1677.62,376 1684.43,382.81 1693.74,382.81 1694.23,383.3 1735.5,383.3 1747.2,395 1810,395 1838.87,366.13 1838.87,350.81 1842.68,347 C29.1@1846,347 ; C29.1@1849.62,344 1882.92,344 U1.12@1915.72,311.21
  other v4: 1730,390
NetC30_1: C30.1 R10.1 U2.13 | length 447.7
  Top Layer w8: v1(1876,983) 1880.97,983 1893.53,970.44 1914.56,970.44 U2.13@1915,970
  Bottom Layer w8: R10.1@1588,1079 1581,1072 1581,1016 1650.23,946.77 1802.5,946.77 1819,963.27 1819,964.32 1831.68,977 C30.1@1838,977 ; C30.1@1838.62,980 1840.12,981.5 1874.5,981.5 v1(1876,983)
  other v4: 1581,1024
NetC31_1: C31.1 R11.1 U1.13 | length 290.8
  Top Layer w10: C31.1@1848.62,300 1850.12,298.5 1886.5,298.5 v1(1888,297) 1890.62,297 1895.75,291.87 U1.13@1911.72,291.87
  Bottom Layer w10: R11.1@1678.62,333 1682.56,333 1703.43,312.13 1717.87,312.13 1731.15,298.85 1886.15,298.85 v1(1888,297)
  other v4: 1725,305
NetC40_1: C40.1 R14.1 R15.1 | length 158.5
  Top Layer w10: v4@1869,1961 1869,1951.92 1884.62,1936.3 R14.1@1884.62,1888 ; R14.1@1892,1889 1919,1889 C40.1@1920,1890 1954.19,1890 1961,1883.19 R15.1@1961,1882.62 R15.1@1961,1878 ; R15.1@1955.87,1871.87 R15.1@1957,1873
  other v4: 1870.45,1957.3
NetC40_2: C40.2 C41.2 U3.11 | length 148.7
  Top Layer w10: v4@1878,1802 1881.5,1798.5 1912.88,1798.5 C41.2@1915.38,1796 1915.38,1847.5 1917.88,1850 C40.2@1920,1850 C40.2@1922,1850 ; C41.2@1920,1791 1924.32,1791 1926.13,1789.19 1926.13,1784.87 1930,1781 1930,1752 ; C40.2@1923,1847.5 C40.2@1927,1847.5
  other v4: 1867,1801
NetC41_1: C41.1 R15.2 U3.10 | length 81.5
  Top Layer w10: U3.10@1950.09,1754.11 1950.09,1761.47 1962.62,1774.01 C41.1@1962.62,1796 ; C41.1@1961,1801 R15.2@1961,1835.38
NetC42_1: C42.1 R16.1 U3.12 | length 182.6
  Top Layer w8: R16.1@1758.62,1771 1809.14,1771 1839.94,1740.21 1839.94,1739.16 1848.1,1731 C42.1@1850,1731
  Top Layer w10: C42.1@1851.68,1728.57 1879.43,1728.57 1910.72,1697.28 U3.12@1910.72,1695.21
NetC43_1: C43.1 R17.1 U3.13 | length 435.3
  Top Layer w10: C43.1@1840.68,1685.25 1843.08,1682.85 1884.15,1682.85 v1(1886,1681) 1888.62,1681 1894.1,1675.52 U3.13@1910.72,1675.52
  Bottom Layer w10: R17.1@1576.62,1548 1753,1548 1883,1678 v1@1883,1679
NetC45_2: C45.2 L1.2 U4.6 | length 105.8
  Bottom Layer w10: L1.2@1735.12,161.11 C45.2@1735.12,114.85 1737.09,112.88 U4.6@1737.09,56.1
NetC47_1: C47.1 R23.1 U4.1 | length 147.1
  Bottom Layer w10: U4.1@1788.27,-46.26 1792.13,-42.41 1792.13,-21.09 1800.6,-12.62 1842.19,-12.62 C47.1@1849,-19.43 ; C47.1@1849,-20.62 C47.1@1849,-19.43 ; R23.1@1902.11,-12.62 1855.81,-12.62 C47.1@1849,-19.43
NetC47_2: C47.2 R24.1 U4.8 | length 151.7
  Bottom Layer w10: U4.8@1788.27,56.1 1791.47,52.9 1791.47,25.96 1800.6,16.83 1842.19,16.83 1849,23.64 C47.2@1849,26.62 R24.1@1902.11,26.62
NetC48_2: C48.2 R25.2 U4.7 | length 221.2
  Bottom Layer w10: R25.2@1589,-4.93 1589,-3.86 1595.81,2.95 1642.36,2.95 1746.5,2.95 1762.68,19.13 U4.7@1762.68,56.1
NetC49_2: C49.2 L3.2 U6.6 | length 89.7
  Bottom Layer w10: C49.2@1698.62,761 1699.24,761.62 L3.2@1699.24,805.87 ; C49.2@1700.3,761.81 1704.8,757.31 U6.6@1704.8,719.08
NetC50_1: C50.1 L2.1 U5.1 | length 117.7
  Bottom Layer w10: U5.1@1417.4,302.73 1417.4,238.12 C50.1@1421.77,233.75 1421.77,187.88 L2.1@1421.02,187.13
NetC51_2: C51.2 R28.1 U5.2 | length 127.3
  Bottom Layer w10: U5.2@1417.4,377.53 1417.4,451.49 C51.2@1419.77,453.86 1418.02,455.61 R28.1@1418.02,503.13
NetC53_1: C53.1 R31.1 U6.1 | length 170.7
  Bottom Layer w10: U6.1@1755.44,604.99 1759.3,608.85 1759.3,628.03 1768.75,637.48 1814.47,637.48 C53.1@1820.69,631.26 1820.69,635.2 1827.5,642.01 1831.43,642.01 1831.64,642.21 1876.5,642.21 1884.72,634 R31.1@1888.65,634
NetC53_2: C53.2 R30.1 U6.8 | length 164.7
  Bottom Layer w10: U6.8@1755.44,707.36 1755.44,683.16 1767.1,671.51 1820.69,671.51 1823.6,668.59 1874.79,668.59 1874.79,669.54 1884.1,669.54 R30.1@1887.54,672.97
NetC54_2: C54.2 R32.1 U6.7 | length 192.8
  Bottom Layer w10: R32.1@1688.62,849 1695.43,842.19 1708.68,842.19 1731.43,819.45 1731.43,815.57 1749.3,797.7 1749.3,793.19 1758.49,784 C54.2@1763,784 ; U6.7@1729.85,707.36 1733.71,711.21 U6.7@1733.71,723 ; U6.7@1729.87,723 U6.7@1731,723 ; U6.7@1729.85,723.03 1729.85,744.37 C54.2@1763,777.52
NetC58_1: C58.1 C59.1 R37.1 U8.8 | length 507
  Bottom Layer w10: R37.1@1355,1498 1360.56,1498 1438.18,1420.38 C58.1@1691,1420.38 ; C58.1@1691,1415 C59.1@1728.62,1415 ; C59.1@1733,1414 1816.43,1414 U8.8@1829.04,1401.39
NetC60_1: C60.1 R35.1 U7.7 | length 125.4
  Bottom Layer w10: U7.7@840.61,2155.2 882,2155.2 ; 882,2155 893.38,2155 894.25,2155.87 898.19,2155.87 905,2162.68 C60.1@905,2166.62 909.62,2162 R35.1@957,2162
NetC60_2: C60.2 R36.1 U7.8 | length 109.9
  Bottom Layer w10: U7.8@840.61,2129.61 C60.2@895.39,2129.61 ; C60.2@905,2119.38 905,2123.32 911.81,2130.13 915.75,2130.13 916.62,2131 R36.1@953,2131
NetC61_1: C61.1 C66.1 R41.1 U8.2 | length 182.7
  Top Layer w10: v1@2006,1371 2010.97,1371 2019.27,1362.7 2037.8,1362.7 R41.1@2051.5,1349
  Bottom Layer w10: U8.2@1962.93,1376.8 1999.2,1376.8 v1@2001,1375 ; v1@2009,1372 2009.36,1372.36 2031.3,1372.36 2045,1386.06 C61.1@2045,1386.5 ; C61.1@2043.8,1375.8 C61.1@2044,1376 ; C61.1@2053,1384 2056,1381 C66.1@2098.5,1381
  other v1: 2005.18,1372.36
NetC61_2: C61.2 C65.1 R45.1 U8.3 | length 220.6
  Top Layer w10: v1@1999,1323 2004.47,1323 2017.77,1309.7 2038.8,1309.7 R45.1@2052.5,1296 ; R45.1@2053.38,1295 R45.1@2056.38,1292
  Bottom Layer w10: U8.3@1958.96,1350.2 1965.69,1350.2 1973.49,1342.41 1974.95,1342.41 1999,1318.36 2042.36,1318.36 C61.2@2044,1320 ; C61.2@2049,1321 C61.2@2053,1321 ; C61.2@2053,1326 2056,1323 C65.1@2100.5,1323
  other v1: 1998.84,1324.2
NetC68_1: C68.1 D4.2 J2.18 R57.2 | length 1119.3
  Top Layer w10: J2.18@969,140 973,140 1012.35,100.65 ; 1013,101 1013.35,100.65 1148.65,100.65 1203,155 1469,155 1523.35,100.65 1643.5,-19.5 1803.88,-19.5 R57.2@1805.38,-18
  Bottom Layer w10: C68.1@966,248 967,247 J2.18@967,146 ; C68.1@971.5,256 971.5,317.5 D4.2@977,323
NetC69_1: C69.1 J2.16 R55.2 | length 177.8
  Bottom Layer w10: C69.1@865,254.5 R55.2@912,254.5 ; J2.16@868,146 868,147 912,191 R55.2@912,254.5 ; R55.2@912,257.38 R55.2@912,254.5 ; R55.2@913,255 912.5,254.5 R55.2@912,254.5
NetC70_1: C70.1 J2.14 R54.2 | length 137.8
  Top Layer w10: J2.14@767,146 C70.1@767,230 ; C70.1@768,230 R54.2@821.76,230
NetC71_1: C71.1 D6.2 J2.12 R53.2 | length 265.2
  Bottom Layer w10: D6.2@651,270 651,262.89 661.78,252.11 C71.1@718.16,252.11 772.11,252.11 R53.2@776,256 ; J2.12@667,146 704.46,183.46 704.46,237.42 C71.1@718.65,251.61
NetC73_1: C73.1 D3.2 J2.10 R51.2 | length 474.5
  Top Layer w10: C73.1@584,244 582.98,244 567,228.02 J2.10@567,146 614,99 614,21.44 657.44,-22 693,-22 R51.2@693.38,-22.38
  Bottom Layer w10: D3.2@547,265 547,263.87 567,243.87 J2.10@567,146
NetC74_1: C74.1 D5.2 J2.8 R50.2 | length 453.3
  Top Layer w10: J2.8@468,146 468,161.87 481,174.87 481,239 C74.1@489,247
  Bottom Layer w10: 447,252 447,244.41 467,224.41 J2.8@467,146 ; J2.8@467,143 515,95 515,-37.62 ; R50.2@515,-50.58 515,-39 ; R50.2@515.99,-50.19 R50.2@522.8,-57 ; R50.2@516.42,-54 R50.2@524.06,-54
NetC75_1: C75.1 D2.2 J2.6 R49.2 | length 267.4
  Top Layer w10: R49.2@323,249.5 C75.1@363,249.5 ; C75.1@363,246 367,242 J2.6@367,146
  Bottom Layer w10: J2.6@367,146 367,254.71 376,263.71 D2.2@376,268
NetC79_1: C79.1 C82.1 C92.1 J7.2 L4.2 R65.2 R67.2 | length 1175.8
  Top Layer w10: v3(403,1441) 400.32,1443.68 400.32,1465.06 C79.1@395,1470.38 439.62,1470.38 R67.2@440,1470 ; C92.1@876,1144 896,1124 918.21,1124 922.21,1120 v3(926,1120)
  Top Layer w20: R65.2@780.99,1061 780.99,888.19 805,864.18 J7.2@805,854 ; C82.1@780.99,1129.5 C82.1@784.49,1133 ; C82.1@823.49,1142 C92.1@847.49,1142
  Top Layer w30: L4.2@713.49,1141 C82.1@784.49,1141 ; R65.2@780.99,1063 C82.1@780.99,1129.5
  POWER w10: v3@403,1436 404.21,1436 409.59,1430.62 409.59,1429.41 719,1120 v3(926,1120)
NetC80_1: C80.1 C81.1 R64.1 U11.2 U11.3 | length 307.4
  Top Layer w20: U11.2@810.68,1362.81 U11.2@810.68,1363 U11.3@810.68,1413 810.84,1412.84 900.33,1412.84 C81.1@900.49,1413
  Top Layer w30: C81.1@901.67,1415.18 926.94,1415.18 962.93,1451.17 C80.1@990.49,1451.17 ; C80.1@965.99,1460.5 R64.1@965.99,1524
NetC84_1: C84.1 C91.1 R72.2 R76.2 U12.1 | length 212
  Top Layer w10: C91.1@324,953 326,955 R76.2@326,1016 ; R72.2@419,1023 R72.2@427,1023
  Top Layer w20: U12.1@279.39,1018.13 319.87,1018.13 R76.2@322,1016 ; R76.2@326,1023 326,1020.81 327.81,1019 C84.1@372,1019 ; C84.1@374,1023.76 374,1021.81 375.81,1020 R72.2@419,1020
NetC84_2: C84.2 R76.1 R77.2 U12.2 | length 144.9
  Top Layer w10: U12.2@279.39,1043.72 299.72,1043.72 R76.1@318,1062 ; R76.1@326,1070.24 326,1120.19 326.81,1121 R77.2@327,1121 ; R76.1@327,1070 373,1070 C84.2@374,1071
NetC85_1: C85.1 C86.1 R73.1 U13.1 U13.2 U13.3 | length 213.2
  Top Layer w10: U13.3@500.51,841 519.19,841 U13.1@538.8,841 ; U13.1@538.88,838.61 538.88,892.37 R73.1@539.51,893 ; U13.1@540.51,840 592.01,840 C85.1@602.51,850.5
  Top Layer w20: C85.1@605.07,851.56 657.45,851.56 C86.1@658.51,852.62
NetC87_1: C87.1 C88.1 C89.1 C90.1 J8.2 R74.2 U13.5 U13.6 U13.7
NetC87_2: C87.2 R74.1 R78.2 U13.8 | length 155.2
  Top Layer w10: U13.8@499.51,789.39 499.51,738.06 503.57,734 C87.2@507.51,734 ; R74.1@511.75,681 511.75,725.24 C87.2@514.51,728 ; C87.2@514.51,729.5 557.01,729.5 R78.2@559.51,732
NetD1_1: D1.1 R34.2 | length 45.2
  Bottom Layer w10: D1.1@1702,1874 1703.33,1874 R34.2@1734.33,1905
NetD7_2: D7.2 R66.2 | length 65.4
  Top Layer w20: D7.2@955,1180 955,1177.5 966.88,1165.62 R66.2@1013,1165.62
NetD8_2: D8.2 R75.1 | length 46.9
  Top Layer w10: D8.2@603.51,582 607.27,582 610.51,578.76 R75.1@610.51,540.24
NetJ2_2: J2.2 R47.2 | length 100.1
  Bottom Layer w10: R47.2@166,245 R47.2@168,245
  Bottom Layer w30: J2.2@166.75,142.25 J2.2@168,141 ; R47.2@168,244.5 167.5,244 167.5,150.5 J2.2@169,149
NetJ3_13: J3.13 R56.2 | length 88.5
  Top Layer w10: R56.2@732,1672 732,1711 J3.13@767,1746
NetJ3_15: J3.15 R80.2 | length 169.4
  Bottom Layer w10: J3.15@867,1746 869,1744 869,1686 921,1634 R80.2@956,1634
NetJ9_1: J9.1 R79.2 U7.5 | length 410.6
  Bottom Layer w10: R79.2@816,2308.38 816,2213 U7.5@818,2211 ; U7.5@828,2204 825.61,2206.39 796.39,2206.39 778,2188 778,2120 861.47,2036.53 861.47,2015.53 J9.1@885,1992 ; U7.5@828,2206.39 U7.5@840.61,2206.39 U7.5@840,2207
NetR4_1: R4.1 U2.14 | length 60.9
  Top Layer w8: R4.1@1858.62,945 1888.62,945 1894.38,950.76 1916.76,950.76 U2.14@1917,951
NetR5_1: R5.1 U1.14 | length 65.5
  Top Layer w10: R5.1@1864.62,261 1892.08,261 1902.08,271 U1.14@1926,271
NetR13_1: R13.1 U3.14 | length 80.1
  Top Layer w10: R13.1@1850.62,1647 1889.08,1647 1898.08,1656 U3.14@1927,1656
NetR33_1: R33.1 R38.1 U7.3 | length 120.3
  Bottom Layer w10: R33.1@558,2215 585.81,2215 586.65,2214.16 607.16,2214.16 R38.1@612,2209.32 ; R38.1@612.68,2207.03 625.97,2193.75 625.97,2193.34 634.65,2184.65 663.35,2184.65 U7.3@666,2182
NetR40_2: R40.2 U8.6 | length 49.2
  Bottom Layer w10: R40.2@1781,1354 1783.8,1351.2 U8.6@1829.07,1351.2
NetR44_1: R44.1 U14.4 | length 205.8
  Top Layer w10: R44.1@732,2181 R44.1@734,2183 ; R44.1@740,2186 742,2188 800,2188 v1(865,2253)
  Bottom Layer w10: v1@869,2255 876.17,2262.17 876.17,2284.79 882.98,2291.6 U14.4@890.82,2291.6
NetR69_2: R69.2 U11.4 | length 61.3
  Top Layer w20: U11.4@810.68,1463 810.68,1523.19 R69.2@811.49,1524
NetR70_1: R70.1 U7.6 U14.2 | length 298.6
  Bottom Layer w10: U7.6@859,2183 860.65,2184.65 877.27,2184.65 896.44,2203.83 926.83,2203.83 946,2223 946,2294.91 967.37,2316.28 970.62,2316.28 983.34,2329 U14.2@993.18,2329 R70.1@1055,2329
nOC: C64.1 J3.10 R43.1 R44.2 U9.12 U10.12 | length 2152.2
  Top Layer w6: v1(1411,757) 1411.31,757.31 1411.31,776.82 U10.12@1411.61,777.13
  Top Layer w10: J3.10@563,1861 567.13,1861 577.52,1871.39 577.52,1875.52 671.5,1969.5 R44.2@671.5,2181 ; R44.2@671.5,2185.5 C64.1@671.5,2237 672,2237.5 R43.1@672,2293 ; v1@1200.5,1293.5 1200.5,1103.5 v1(1201,1103) ; v1(1412,1067) 1415.02,1070.02 1415.02,1090.31 1415.35,1090.63 U9.12@1415.35,1091.54
  POWER w10: v1(1411,757) 1427,773 1427,1052 v1(1412,1067)
  Bottom Layer w10: J3.10@567,1846 620,1793 684.14,1793 721.65,1755.49 721.65,1703.35 1129,1296 v1(1200,1296) ; v1(1201,1103) 1205.43,1103 1211.43,1097 1382,1097 v1(1412,1067)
